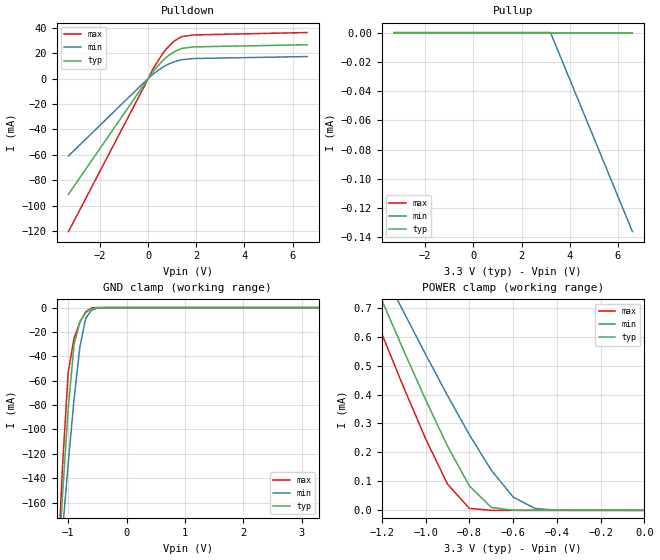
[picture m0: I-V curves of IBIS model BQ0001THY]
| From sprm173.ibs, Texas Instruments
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[Model]   BQ0001THY
Model_type   I/O
Vinh = 2.00
Vinl = 0.80
Enable   Active-Low
Polarity   Non-Inverting
| signals   A, GZ, Y
Vmeas = 1.5
|   typ   min   max
C_comp   3.010p   2.992p   3.013p
|   typ   min   max
[Temperature Range]   25   -40   125
|   typ   min   max
[Voltage Range]   3.30V   3.00V   3.60V
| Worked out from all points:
|   slope of the pulldown table from 0 to 0.495 V, typ, clamps not added: 41 ohm
|   GND clamp passes 1 mA (typ) near -0.60 V on its own axis
|   POWER clamp passes 1 mA (typ) near -1.35 V on its own axis
[Pulldown]
|   Voltage   I(typ)   I(min)   I(max)
-3.3V     -91.05mA   -60.84mA   -120.5mA
-200mV    -5.672mA   -3.678mA   -7.665mA
200mV     5.407mA    3.426mA    7.44mA
600mV     14.11mA    8.921mA    19.51mA
800mV     17.47mA    11.02mA    24.23mA
1.1V      21.35mA    13.4mA     29.79mA
1.4V      23.79mA    14.9mA     33.15mA
1.9V      25.02mA    15.87mA    34.43mA
6.6V      26.68mA    17.37mA    36.3mA
[GND_clamp]
|   Voltage   I(typ)   I(min)   I(max)
-3.3V     -2.106A    -1.593A    -2.727A
-1.2V     -236.1mA   -244.2mA   -235.6mA
-1.1V     -156mA     -185mA     -132.5mA
-1V       -83.14mA   -128mA     -53.25mA
-900mV    -30.46mA   -75.42mA   -25.15mA
-800mV    -11.6mA    -32.29mA   -12.2mA
-700mV    -4.267mA   -8.804mA   -3.591mA
-600mV    -833.7uA   -2.113mA   -410.9uA
-500mV    -76.39uA   -376.6uA   -19.22uA
-400mV    -4.268uA   -46.15uA   -428.2nA
3.3V      133.2pA    31.97nA    133.2pA
[Pullup]
|   Voltage   I(typ)   I(min)   I(max)
-3.3V     0A         0A         0A
3.2V      0A         0A         0A
5.9V      0A         -108uA     0A
6.6V      0A         -136uA     0A
[POWER_clamp]
|   Voltage   I(typ)   I(min)   I(max)
-3.3V     4.588mA    4.102mA    4.731mA
-1.3V     903uA      983.6uA    798.1uA
-1.2V     725.9uA    833.2uA    609.3uA
-1.1V     551.6uA    684.7uA    424.5uA
-1V       382.3uA    538.7uA    247.4uA
-900mV    222.2uA    396.7uA    90.8uA
-800mV    84.67uA    261.3uA    6.783uA
-700mV    10.3uA     138.9uA    73.81nA
-600mV    329.8nA    46.05uA    888.2pA
-500mV    8.482nA    6.46uA     177.6pA
-400mV    444.1pA    466.9nA    177.6pA
0V        0A         0A         0A
[Ramp]
|   I(typ)   I(min)   I(max)
dV/dt_r   0.028/4.234n   0.027/6.763n   0.030/2.474n
dV/dt_f   1.970/4.234n   1.782/6.763n   2.154/2.474n
R_load = 25000ohms
